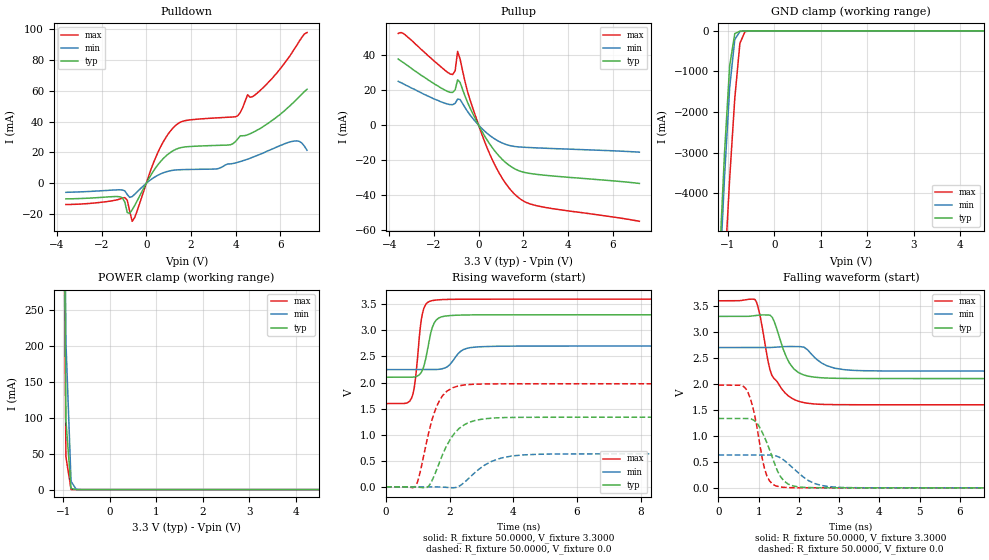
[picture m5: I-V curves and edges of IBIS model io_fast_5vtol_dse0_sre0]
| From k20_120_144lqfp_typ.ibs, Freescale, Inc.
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[Model]  io_fast_5vtol_dse0_sre0
|   Model io_fast_5vtol_dse0_sre0
| Library cells for typ/min/max conditions are connected as defined below:
|  pad - External Pad
|  ipp_do - Core Input
|  ipp_obe - Output Buffer Enable
|  esd_boost - vdd_s_3v
|  esd_bus - vdd_s_3v
|  ipp_ame - vss_s_lv
|  ipp_dse - vss_s_lv
|  ipp_ina40a_5vtol - NC
|  ipp_ina40b_5vtol - NC
|  ipp_ina_5vtol - NC
|  ipp_ina_mux_3v - NC
|  ipp_ind - NC
|  ipp_ind_3v - NC
|  ipp_pue - vss_s_lv
|  ipp_sre - vss_s_lv
|  tie_3v - vdd_s_3v
|  tie_hi - vdd_s_lv
|  vbuf_3v - vdd_s_3v
|  vdd_bulk_lv - vdd_s_lv
|  vdd_s_3v - vdd_s_3v
|  vdd_s_lv - vdd_s_lv
|  vss_bulk - vss_s_3v
|  vss_s_3v - vss_s_3v
|  vss_s_lv - vss_s_lv
| All other pins connected to ground
Model_type I/O
Polarity   Non-Inverting
Enable   Active-High
Vinl =   1.1550V
Vinh =   2.3100V
Vmeas =  1.6500V
Cref =   25.0000pF
Rref =   50.0000
Vref =   0.0V
C_comp   4.8314pF   4.6080pF   5.0799pF
[Temperature Range]   25.0000   0.1250k   -40.0000
[Voltage Range]   3.3000V   2.7000V   3.6000V
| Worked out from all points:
|   slope of the pulldown table from 0 to 0.495 V, typ, clamps not added: 43 ohm
|   slope of the pullup table from 0 to 0.495 V, typ, clamps not added: 46.1 ohm
|   GND clamp passes 1 mA (typ) near -0.54 V on its own axis
|   POWER clamp passes 1 mA (typ) near -0.79 V on its own axis
|   rising waveform, R_fixture 50.0000, V_fixture 3.3000: 20-80 % time 255ps typ, 377ps min, 200ps max; typ from 2.1 V to 3.3 V
|   rising waveform, R_fixture 50.0000, V_fixture 0.0: 20-80 % time 665ps typ, 865ps min, 506ps max; typ from 0 V to 1.33 V
|   falling waveform, R_fixture 50.0000, V_fixture 3.3000: 20-80 % time 373ps typ, 473ps min, 433ps max; typ from 3.3 V to 2.1 V
|   falling waveform, R_fixture 50.0000, V_fixture 0.0: 20-80 % time 418ps typ, 602ps min, 293ps max; typ from 1.33 V to 0 V
[Pulldown]
|Voltage   I(typ)   I(min)   I(max)
-3.6V     -10.1mA    -5.85mA    -13.73mA
-1.29V    -8.593mA   -4.245mA   -10.67mA
-960mV    -12.21mA   -4.926mA   -9.278mA
-850mV    -18.97mA   -7.293mA   -11mA
-630mV    -17.18mA   -8.599mA   -24.63mA
470mV     11.04mA    4.829mA    18.36mA
1.24V     21.41mA    8.514mA    36.48mA
4.1V      28.81mA    13.6mA     43.8mA
4.54V     31.46mA    15.6mA     57.37mA
5.2V      36.4mA     19.4mA     61.5mA
6.63V     52.9mA     27.4mA     87mA
7.2V      60.9mA     21.4mA     97.7mA
[Pullup]
|Voltage   I(typ)   I(min)   I(max)
-3.6V     37.7mA     25mA       52.3mA
-3.36V    35.6mA     23.5mA     52.2mA
-1.27V    18.7mA     11.69mA    29.17mA
-1.05V    20.11mA    12.44mA    31.01mA
-940mV    25.83mA    14.83mA    42.08mA
-830mV    24.4mA     14.62mA    37.76mA
-390mV    9.99mA     5.918mA    14.73mA
380mV     -8.486mA   -4.67mA    -12.95mA
1.04V     -19.31mA   -10.1mA    -29.93mA
1.81V     -26.05mA   -12.44mA   -41.62mA
2.8V      -28.38mA   -13.1mA    -46.51mA
7.2V      -33.28mA   -15.44mA   -54.88mA
[GND_clamp]
|Voltage   I(typ)   I(min)   I(max)
-3.6V     -73.34A    -73.38A    -74.77A
-1.18V    -5.66A     -6.206A    -8.642A
-1.07V    -2.998A    -3.593A    -5.955A
-960mV    -859.3mA   -1.399A    -3.637A
-850mV    -67.61mA   -213.2mA   -1.663A
-740mV    -7.668mA   -16.88mA   -304.8mA
-630mV    -2.587mA   -2.229mA   -18.83mA
-520mV    -662.1uA   -532.3uA   -1.741mA
7.2V      0A         0A         0A
[POWER_clamp]
|Voltage   I(typ)   I(min)   I(max)
-3.6V     45.85A     45.45A     46.17A
-1.05V    1.004A     1.14A      941.6mA
-940mV    96.57mA    206.1mA    45.73mA
-830mV    1.646mA    11.48mA    218.1uA
-720mV    22.84uA    474.3uA    919.1nA
-610mV    316.6nA    19.24uA    4.178nA
7.2V      0A         0A         0A
[Ramp]
| variable   typ   min   max
dV/dt_r  0.8010/0.6647n   0.3796/0.8647n   1.1859/0.5065n
dV/dt_f  0.7186/0.3727n   0.2713/0.4726n   1.2013/0.4330n
R_load = 50.0000
[Rising Waveform]
R_fixture= 50.0000
V_fixture= 3.3000
V_fixture_min= 2.7000
V_fixture_max= 3.6000
|time   V(typ)   V(min)   V(max)
0s        2.102V     2.248V     1.597V
795.1ps   2.103V     2.248V     1.695V
926.1ps   2.111V     2.248V     2.09V
1.07ns    2.167V     2.248V     3.039V
1.136ns   2.232V     2.248V     3.311V
1.487ns   3.109V     2.248V     3.576V
1.838ns   3.273V     2.278V     3.593V
2.428ns   3.295V     2.632V     3.598V
2.961ns   3.299V     2.687V     3.599V
20ns      3.3V       2.7V       3.6V
[Rising Waveform]
R_fixture= 50.0000
V_fixture= 0.0
V_fixture_min= 0.0
V_fixture_max= 0.0
|time   V(typ)   V(min)   V(max)
0s        1.032nV    103.3nV    632.6pV
921.7ps   -2.761mV   362.3nV    12.95mV
1.03ns    -8.03mV    -13.36uV   183.8mV
1.333ns   10.37mV    726.7uV    1.029V
1.66ns    444.4mV    -2.798mV   1.637V
2.024ns   921.1mV    -16.98mV   1.876V
2.477ns   1.197V     94.21mV    1.956V
3.318ns   1.317V     488.6mV    1.974V
4.282ns   1.333V     610.8mV    1.976V
20ns      1.335V     632.7mV    1.976V
[Falling Waveform]
R_fixture= 50.0000
V_fixture= 3.3000
V_fixture_min= 2.7000
V_fixture_max= 3.6000
|time   V(typ)   V(min)   V(max)
0s        3.3V       2.7V       3.6V
906.2ps   3.314V     2.7V       3.624V
1.011ns   3.325V     2.7V       3.393V
1.217ns   3.327V     2.699V     2.494V
1.328ns   3.287V     2.703V     2.161V
1.762ns   2.403V     2.72V      1.756V
2.176ns   2.161V     2.678V     1.632V
2.692ns   2.113V     2.35V      1.604V
3.545ns   2.104V     2.255V     1.599V
20ns      2.102V     2.248V     1.598V
[Falling Waveform]
R_fixture= 50.0000
V_fixture= 0.0
V_fixture_min= 0.0
V_fixture_max= 0.0
|time   V(typ)   V(min)   V(max)
0s        1.335V     632.8mV    1.977V
699.3ps   1.335V     632.8mV    1.885V
894.7ps   1.292V     632.9mV    1.416V
1.088ns   1.067V     631.9mV    559mV
1.198ns   877.1mV    632.3mV    241.3mV
1.331ns   598.7mV    628.3mV    79.77mV
1.596ns   162.9mV    549.5mV    11.1mV
2.243ns   5.566mV    136.8mV    1.036mV
2.944ns   846uV      12.48mV    681.7uV
20ns      186uV      99.59uV    200.8uV
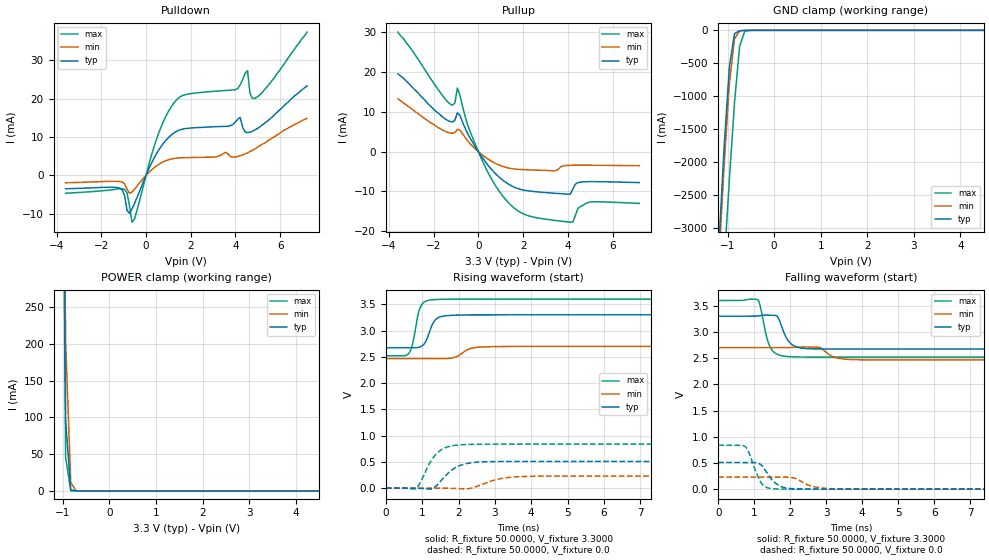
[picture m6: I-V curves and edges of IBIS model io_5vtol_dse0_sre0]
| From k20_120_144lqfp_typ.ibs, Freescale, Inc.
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[Model]  io_5vtol_dse0_sre0
|   Model io_5vtol_dse0_sre0
| Library cells for typ/min/max conditions are connected as defined below:
|  pad - External Pad
|  ipp_do - Core Input
|  ipp_obe - Output Buffer Enable
|  esd_boost - vdd_s_3v
|  esd_bus - vdd_s_3v
|  ipp_ame - vss_s_lv
|  ipp_dse - vss_s_lv
|  ipp_ina40a_5vtol - NC
|  ipp_ina40b_5vtol - NC
|  ipp_ina_5vtol - NC
|  ipp_ina_mux_3v - NC
|  ipp_ind - NC
|  ipp_ind_3v - NC
|  ipp_pue - vss_s_lv
|  ipp_sre - vss_s_lv
|  tie_3v - vdd_s_3v
|  tie_hi - vdd_s_lv
|  vbuf_3v - vdd_s_3v
|  vdd_bulk_lv - vdd_s_lv
|  vdd_s_3v - vdd_s_3v
|  vdd_s_lv - vdd_s_lv
|  vss_bulk - vss_s_3v
|  vss_s_3v - vss_s_3v
|  vss_s_lv - vss_s_lv
| All other pins connected to ground
Model_type I/O
Polarity   Non-Inverting
Enable   Active-High
Vinl =   1.1550V
Vinh =   2.3100V
Vmeas =  1.6500V
Cref =   25.0000pF
Rref =   50.0000
Vref =   0.0V
C_comp   2.9184pF   2.7887pF   3.0744pF
[Temperature Range]   25.0000   0.1250k   -40.0000
[Voltage Range]   3.3000V   2.7000V   3.6000V
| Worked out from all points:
|   slope of the pulldown table from 0 to 0.495 V, typ, clamps not added: 83.9 ohm
|   slope of the pullup table from 0 to 0.495 V, typ, clamps not added: 129 ohm
|   GND clamp passes 1 mA (typ) near -0.58 V on its own axis
|   POWER clamp passes 1 mA (typ) near -0.79 V on its own axis
|   rising waveform, R_fixture 50.0000, V_fixture 3.3000: 20-80 % time 227ps typ, 335ps min, 184ps max; typ from 2.67 V to 3.3 V
|   rising waveform, R_fixture 50.0000, V_fixture 0.0: 20-80 % time 495ps typ, 644ps min, 421ps max; typ from 0 V to 0.509 V
|   falling waveform, R_fixture 50.0000, V_fixture 3.3000: 20-80 % time 261ps typ, 322ps min, 224ps max; typ from 3.3 V to 2.67 V
|   falling waveform, R_fixture 50.0000, V_fixture 0.0: 20-80 % time 356ps typ, 458ps min, 285ps max; typ from 0.509 V to 0 V
[Pulldown]
|Voltage   I(typ)   I(min)   I(max)
-3.6V     -3.51mA    -1.95mA    -4.66mA
-1.29V    -3.199mA   -1.569mA   -3.563mA
-960mV    -5.372mA   -2.232mA   -3.734mA
-850mV    -9.168mA   -3.652mA   -4.602mA
-630mV    -8.788mA   -4.388mA   -12.21mA
580mV     6.709mA    2.897mA    11.22mA
1.35V     11.41mA    4.463mA    19.56mA
4.21V     15.06mA    5.09mA     23.54mA
4.54V     11.12mA    5.8mA      27.24mA
4.65V     11.23mA    6.2mA      21.29mA
4.87V     11.8mA     6.9mA      20.05mA
7.2V      23.3mA     14.8mA     37.3mA
[Pullup]
|Voltage   I(typ)   I(min)   I(max)
-3.6V     19.6mA     13.3mA     30.1mA
-1.38V    7.89mA     4.9mA      12.58mA
-1.05V    7.911mA    4.85mA     12.3mA
-940mV    9.791mA    5.619mA    16.02mA
-500mV    4.763mA    2.871mA    7.069mA
270mV     -2.225mA   -1.226mA   -3.408mA
930mV     -6.397mA   -3.361mA   -9.943mA
1.7V      -9.133mA   -4.394mA   -14.6mA
4.12V     -10.63mA   -3.413mA   -17.73mA
4.34V     -8.156mA   -3.39mA    -16mA
4.89V     -7.539mA   -3.4mA     -12.8mA
7.2V      -7.77mA    -3.53mA    -13mA
[GND_clamp]
|Voltage   I(typ)   I(min)   I(max)
-3.6V     -39.79A    -39.79A    -41.16A
-1.18V    -3.193A    -3.445A    -4.927A
-1.07V    -1.746A    -2.022A    -3.54A
-960mV    -554.7mA   -809.6mA   -2.265A
-850mV    -51.43mA   -127.1mA   -1.104A
-740mV    -5.185mA   -9.693mA   -242.4mA
-630mV    -1.474mA   -1.24mA    -14.98mA
-520mV    -384.8uA   -304.4uA   -1.148mA
7.2V      0A         0A         0A
[POWER_clamp]
|Voltage   I(typ)   I(min)   I(max)
-3.6V     45.62A     45.23A     45.93A
-1.05V    987.4mA    1.121A     927.4mA
-940mV    95.32mA    202.8mA    45.29mA
-830mV    1.645mA    11.46mA    218.1uA
-720mV    22.84uA    474.3uA    919.1nA
-610mV    316.6nA    19.24uA    4.178nA
7.2V      0A         0A         0A
[Ramp]
| variable   typ   min   max
dV/dt_r  0.3054/0.4951n   0.1382/0.6447n   0.5027/0.4214n
dV/dt_f  0.3761/0.2609n   0.1405/0.3219n   0.6484/0.2238n
R_load = 50.0000
[Rising Waveform]
R_fixture= 50.0000
V_fixture= 3.3000
V_fixture_min= 2.7000
V_fixture_max= 3.6000
|time   V(typ)   V(min)   V(max)
0s        2.673V     2.466V     2.519V
634.4ps   2.673V     2.466V     2.567V
742.6ps   2.673V     2.466V     2.76V
943.5ps   2.689V     2.466V     3.438V
1.083ns   2.772V     2.466V     3.554V
1.335ns   3.181V     2.466V     3.59V
1.642ns   3.282V     2.467V     3.597V
2.354ns   3.299V     2.664V     3.599V
3.024ns   3.3V       2.695V     3.599V
20ns      3.3V       2.7V       3.6V
[Rising Waveform]
R_fixture= 50.0000
V_fixture= 0.0
V_fixture_min= 0.0
V_fixture_max= 0.0
|time   V(typ)   V(min)   V(max)
0s        1.227nV    115.8nV    934.1pV
813ps     -20.38uV   2.032uV    -12.84mV
916.7ps   -3.205mV   -6.261uV   64.05mV
1.228ns   -19.69mV   95.28uV    500.1mV
1.393ns   47.23mV    253.2uV    657.8mV
1.746ns   307.5mV    -2.338mV   794.2mV
2.14ns    453.7mV    -15.56mV   829.7mV
3.137ns   507.4mV    178mV      837.1mV
3.945ns   508.5mV    225.3mV    837.3mV
20ns      508.9mV    230.3mV    837.8mV
[Falling Waveform]
R_fixture= 50.0000
V_fixture= 3.3000
V_fixture_min= 2.7000
V_fixture_max= 3.6000
|time   V(typ)   V(min)   V(max)
0s        3.3V       2.7V       3.6V
1.091ns   3.304V     2.7V       3.619V
1.155ns   3.31V      2.7V       3.527V
1.336ns   3.322V     2.7V       2.928V
1.438ns   3.32V      2.7V       2.716V
1.658ns   3.286V     2.7V       2.568V
1.946ns   2.83V      2.701V     2.529V
2.341ns   2.688V     2.714V     2.522V
3.893ns   2.674V     2.469V     2.52V
20ns      2.673V     2.466V     2.519V
[Falling Waveform]
R_fixture= 50.0000
V_fixture= 0.0
V_fixture_min= 0.0
V_fixture_max= 0.0
|time   V(typ)   V(min)   V(max)
0s        509mV      230.4mV    838mV
753.1ps   509mV      230.4mV    810.7mV
842ps     508.8mV    230.4mV    715.3mV
1.17ns    474.4mV    230.4mV    143.5mV
1.301ns   367.7mV    230.4mV    46.27mV
1.546ns   142.6mV    230.3mV    6.11mV
1.978ns   12.44mV    226.9mV    751.3uV
2.663ns   575.9uV    45.86mV    441.2uV
3.36ns    300.9uV    4.073mV    339uV
20ns      62.85uV    40.98uV    94.9uV
